VERSION 5.7 ;
  NOWIREEXTENSIONATPIN ON ;
  DIVIDERCHAR "/" ;
  BUSBITCHARS "[]" ;
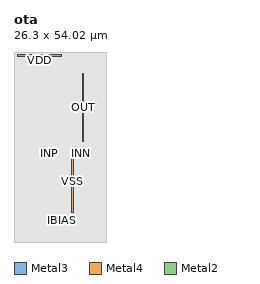
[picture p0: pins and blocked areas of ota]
MACRO ota
  CLASS BLOCK ;
  FOREIGN ota ;
  ORIGIN 13.260 3.940 ;
  SIZE 26.300 BY 54.020 ;
  PIN IBIAS
    ANTENNAGATEAREA 8.000000 ;
    ANTENNADIFFAREA 1.120000 ;
    PORT
      LAYER Metal3 ;
        RECT -0.600 2.020 1.160 2.300 ;
    END
  END IBIAS
  PIN OUT
    ANTENNADIFFAREA 2.800000 ;
    PORT
      LAYER Metal4 ;
        RECT 6.260 24.740 6.540 43.840 ;
    END
  END OUT
  PIN INN
    ANTENNAGATEAREA 2.400000 ;
    PORT
      LAYER Metal2 ;
        RECT 5.530 21.065 5.810 21.345 ;
    END
  END INN
  PIN INP
    ANTENNAGATEAREA 2.400000 ;
    PORT
      LAYER Metal2 ;
        RECT -3.410 21.065 -3.130 21.345 ;
    END
  END INP
  PIN VSS
    USE GROUND ;
    PORT
      LAYER Metal4 ;
        RECT 3.060 4.340 3.620 22.420 ;
    END
  END VSS
  PIN VDD
    USE POWER ;
    PORT
      LAYER Metal3 ;
        RECT -12.240 48.800 0.140 49.360 ;
    END
  END VDD
  OBS
      LAYER Nwell ;
        RECT -10.040 0.000 10.040 45.790 ;
      LAYER Metal1 ;
        RECT -9.810 0.210 9.810 45.580 ;
      LAYER Metal2 ;
        RECT -10.170 21.645 9.810 47.290 ;
        RECT -10.170 20.765 -3.710 21.645 ;
        RECT -2.830 20.765 5.230 21.645 ;
        RECT 6.110 20.765 9.810 21.645 ;
        RECT -10.170 0.210 9.810 20.765 ;
      LAYER Metal3 ;
        RECT -13.260 48.500 -12.540 49.360 ;
        RECT 0.440 48.500 12.800 49.360 ;
        RECT -13.260 2.600 12.800 48.500 ;
        RECT -13.260 1.720 -0.900 2.600 ;
        RECT 1.460 1.720 12.800 2.600 ;
        RECT -13.260 -3.220 12.800 1.720 ;
      LAYER Metal4 ;
        RECT -13.230 44.140 12.770 49.330 ;
        RECT -13.230 24.440 5.960 44.140 ;
        RECT 6.840 24.440 12.770 44.140 ;
        RECT -13.230 22.720 12.770 24.440 ;
        RECT -13.230 4.040 2.760 22.720 ;
        RECT 3.920 4.040 12.770 22.720 ;
        RECT -13.230 -3.190 12.770 4.040 ;
      LAYER Metal5 ;
        RECT -13.230 -3.940 13.040 50.080 ;
  END
END ota
END LIBRARY

